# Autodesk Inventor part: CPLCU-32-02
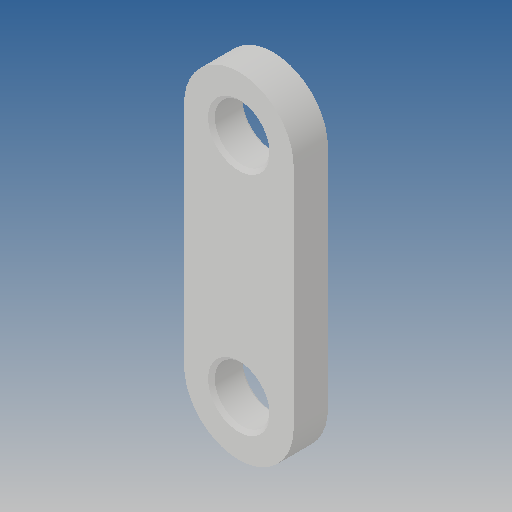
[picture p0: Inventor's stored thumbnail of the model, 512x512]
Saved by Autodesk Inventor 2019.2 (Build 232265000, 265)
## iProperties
Created: 2010-03
Part Number: CPLCU-32-02
Material: Ogólny
Document SubType Name: Modeling
Designer: CADENGINEERING4
Density: 1 g/cm^3
Appearance: Domyślna
Author: CADENGINEERING4
Revision Number: 1LAST_VERSION
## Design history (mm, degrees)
feature "Baza1"
node "Bryła1"
